VERSION 5.8 ;
BUSBITCHARS "[]" ;
DIVIDERCHAR "/" ;
UNITS
    DATABASE MICRONS 1000 ;
END UNITS

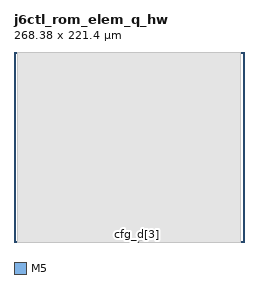
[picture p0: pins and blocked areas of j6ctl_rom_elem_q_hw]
MACRO j6ctl_rom_elem_q_hw
  FOREIGN ot_v41_rom_elem_q_qxpq_w10_gb_hw 0 0 ;
  CLASS BLOCK ;
  SIZE 268.38 BY 221.4 ;
  PIN bank_free
    DIRECTION OUTPUT ;
    USE SIGNAL ;
    PORT
      LAYER M5 ;
        RECT  142.752 0 142.776 0.084 ;
    END
  END bank_free
  PIN cfg_a[0]
    DIRECTION INPUT ;
    USE SIGNAL ;
    PORT
      LAYER M5 ;
        RECT  142.848 0 142.872 0.084 ;
    END
  END cfg_a[0]
  PIN cfg_a[1]
    DIRECTION INPUT ;
    USE SIGNAL ;
    PORT
      LAYER M5 ;
        RECT  142.944 0 142.968 0.084 ;
    END
  END cfg_a[1]
  PIN cfg_a[2]
    DIRECTION INPUT ;
    USE SIGNAL ;
    PORT
      LAYER M5 ;
        RECT  143.04 0 143.064 0.084 ;
    END
  END cfg_a[2]
  PIN cfg_a[3]
    DIRECTION INPUT ;
    USE SIGNAL ;
    PORT
      LAYER M5 ;
        RECT  143.136 0 143.16 0.084 ;
    END
  END cfg_a[3]
  PIN cfg_a[4]
    DIRECTION INPUT ;
    USE SIGNAL ;
    PORT
      LAYER M5 ;
        RECT  143.232 0 143.256 0.084 ;
    END
  END cfg_a[4]
  PIN cfg_d[0]
    DIRECTION INPUT ;
    USE SIGNAL ;
    PORT
      LAYER M5 ;
        RECT  143.328 0 143.352 0.084 ;
    END
  END cfg_d[0]
  PIN cfg_d[10]
    DIRECTION INPUT ;
    USE SIGNAL ;
    PORT
      LAYER M5 ;
        RECT  144.288 0 144.312 0.084 ;
    END
  END cfg_d[10]
  PIN cfg_d[11]
    DIRECTION INPUT ;
    USE SIGNAL ;
    PORT
      LAYER M5 ;
        RECT  144.384 0 144.408 0.084 ;
    END
  END cfg_d[11]
  PIN cfg_d[12]
    DIRECTION INPUT ;
    USE SIGNAL ;
    PORT
      LAYER M5 ;
        RECT  144.48 0 144.504 0.084 ;
    END
  END cfg_d[12]
  PIN cfg_d[13]
    DIRECTION INPUT ;
    USE SIGNAL ;
    PORT
      LAYER M5 ;
        RECT  144.576 0 144.6 0.084 ;
    END
  END cfg_d[13]
  PIN cfg_d[14]
    DIRECTION INPUT ;
    USE SIGNAL ;
    PORT
      LAYER M5 ;
        RECT  144.672 0 144.696 0.084 ;
    END
  END cfg_d[14]
  PIN cfg_d[15]
    DIRECTION INPUT ;
    USE SIGNAL ;
    PORT
      LAYER M5 ;
        RECT  144.768 0 144.792 0.084 ;
    END
  END cfg_d[15]
  PIN cfg_d[16]
    DIRECTION INPUT ;
    USE SIGNAL ;
    PORT
      LAYER M5 ;
        RECT  144.864 0 144.888 0.084 ;
    END
  END cfg_d[16]
  PIN cfg_d[17]
    DIRECTION INPUT ;
    USE SIGNAL ;
    PORT
      LAYER M5 ;
        RECT  144.96 0 144.984 0.084 ;
    END
  END cfg_d[17]
  PIN cfg_d[1]
    DIRECTION INPUT ;
    USE SIGNAL ;
    PORT
      LAYER M5 ;
        RECT  143.424 0 143.448 0.084 ;
    END
  END cfg_d[1]
  PIN cfg_d[2]
    DIRECTION INPUT ;
    USE SIGNAL ;
    PORT
      LAYER M5 ;
        RECT  143.52 0 143.544 0.084 ;
    END
  END cfg_d[2]
  PIN cfg_d[3]
    DIRECTION INPUT ;
    USE SIGNAL ;
    PORT
      LAYER M5 ;
        RECT  143.616 0 143.64 0.084 ;
    END
  END cfg_d[3]
  PIN cfg_d[4]
    DIRECTION INPUT ;
    USE SIGNAL ;
    PORT
      LAYER M5 ;
        RECT  143.712 0 143.736 0.084 ;
    END
  END cfg_d[4]
  PIN cfg_d[5]
    DIRECTION INPUT ;
    USE SIGNAL ;
    PORT
      LAYER M5 ;
        RECT  143.808 0 143.832 0.084 ;
    END
  END cfg_d[5]
  PIN cfg_d[6]
    DIRECTION INPUT ;
    USE SIGNAL ;
    PORT
      LAYER M5 ;
        RECT  143.904 0 143.928 0.084 ;
    END
  END cfg_d[6]
  PIN cfg_d[7]
    DIRECTION INPUT ;
    USE SIGNAL ;
    PORT
      LAYER M5 ;
        RECT  144 0 144.024 0.084 ;
    END
  END cfg_d[7]
  PIN cfg_d[8]
    DIRECTION INPUT ;
    USE SIGNAL ;
    PORT
      LAYER M5 ;
        RECT  144.096 0 144.12 0.084 ;
    END
  END cfg_d[8]
  PIN cfg_d[9]
    DIRECTION INPUT ;
    USE SIGNAL ;
    PORT
      LAYER M5 ;
        RECT  144.192 0 144.216 0.084 ;
    END
  END cfg_d[9]
  OBS
    LAYER RVTN ;
     RECT  4.32 0 264.06 221.4 ;
    LAYER RVTP ;
     RECT  4.32 0 264.06 221.4 ;
    LAYER M1 ;
     RECT  4.32 0 264.06 221.4 ;
    LAYER M2 ;
     RECT  4.32 0 264.06 221.4 ;
    LAYER M3 ;
     RECT  4.32 0 264.06 221.4 ;
    LAYER M4 ;
     RECT  141.109 1.056 141.829 1.08 ;
     RECT  140.785 0.048 142.081 0.072 ;
     RECT  141.505 0.192 142.081 0.216 ;
     RECT  141.829 1.056 142.883 1.128 ;
     RECT 142.0810 0.1950 142.9130 0.2160 ;
     RECT 142.0810 0.0480 142.6410 0.1950 ;
     RECT  142.297 0.528 143.053 0.552 ;
     RECT  142.933 1.728 143.057 1.752 ;
     RECT  142.883 1.056 143.459 1.08 ;
     RECT  143.221 1.728 143.597 1.752 ;
     RECT  142.189 0.336 143.629 0.36 ;
     RECT  143.053 0.48 143.629 0.552 ;
     RECT  143.629 0.336 143.651 0.552 ;
     RECT  143.651 0.336 143.653 0.504 ;
     RECT  140.713 0.816 143.747 0.84 ;
     RECT 143.6530 0.1950 143.8130 0.5040 ;
     RECT 143.8130 0.1950 143.8570 0.5040 ;
     RECT  143.665 1.104 143.917 1.128 ;
     RECT  143.857 0.24 144.035 0.504 ;
     RECT  144.035 0.24 144.131 0.264 ;
     RECT  144.035 0.432 144.323 0.504 ;
     RECT  143.917 1.056 144.515 1.128 ;
     RECT  144.515 1.056 144.611 1.08 ;
     RECT  143.773 1.68 144.661 1.704 ;
     RECT  144.323 0.432 144.709 0.456 ;
     RECT  144.661 1.68 144.949 1.752 ;
     RECT  144.949 1.68 144.997 1.8 ;
     RECT  144.709 0.432 145.045 0.552 ;
     RECT  144.997 1.584 145.141 1.8 ;
     RECT  143.521 1.968 146.531 1.992 ;
     RECT  144.757 1.152 146.549 1.176 ;
     RECT  144.889 1.392 148.355 1.416 ;
     RECT 142.6410 0.0480 142.8870 0.0720 ;
     RECT 142.6410 0.1440 142.8870 0.1680 ;
     RECT 142.6410 0.1920 142.8870 0.1950 ;
     RECT 142.7210 0.0960 142.8050 0.1200 ;
     RECT 142.7370 0.0480 142.9830 0.0720 ;
     RECT 142.7370 0.0960 142.8050 0.1200 ;
     RECT 142.7370 0.1440 142.9830 0.1680 ;
     RECT 142.7370 0.1920 142.9130 0.1950 ;
     RECT 142.8330 0.0480 143.0790 0.0720 ;
     RECT 142.8330 0.1440 143.0790 0.1680 ;
     RECT 142.8330 0.1920 142.9130 0.1950 ;
     RECT 142.8730 0.0960 142.8870 0.1200 ;
     RECT 142.8730 0.0960 142.9830 0.1200 ;
     RECT 142.8730 0.0960 143.0790 0.1200 ;
     RECT 142.9290 0.0480 143.1750 0.0720 ;
     RECT 142.9290 0.0960 143.1750 0.1200 ;
     RECT 142.9290 0.1440 143.1750 0.1680 ;
     RECT 143.0250 0.0480 143.2710 0.0720 ;
     RECT 143.0250 0.0960 143.2710 0.1200 ;
     RECT 143.0250 0.1440 143.2710 0.1680 ;
     RECT 143.1210 0.0480 143.3670 0.0720 ;
     RECT 143.1210 0.0960 143.3670 0.1200 ;
     RECT 143.1210 0.1440 143.3670 0.1680 ;
     RECT 143.2170 0.0480 143.4630 0.0720 ;
     RECT 143.2170 0.0960 143.4630 0.1200 ;
     RECT 143.2170 0.1440 143.4630 0.1680 ;
     RECT 143.3130 0.0480 143.5590 0.0720 ;
     RECT 143.3130 0.0960 143.5590 0.1200 ;
     RECT 143.3130 0.1440 143.5590 0.1680 ;
     RECT 143.4090 0.0480 143.6550 0.0720 ;
     RECT 143.4090 0.0960 143.6550 0.1200 ;
     RECT 143.4090 0.1440 143.6550 0.1680 ;
     RECT 143.5050 0.0480 143.7510 0.0720 ;
     RECT 143.5050 0.0960 143.7510 0.1200 ;
     RECT 143.5050 0.1440 143.6990 0.1680 ;
     RECT 143.6010 0.0480 143.8130 0.0720 ;
     RECT 143.6010 0.0960 143.8470 0.1200 ;
     RECT 143.6010 0.1440 143.6990 0.1680 ;
     RECT 143.6970 0.0480 143.8130 0.0720 ;
     RECT 143.6970 0.0960 143.9390 0.1200 ;
     RECT 143.6970 0.1440 143.6990 0.1680 ;
     RECT 143.7730 0.1440 143.8470 0.1680 ;
     RECT 143.7730 0.1440 143.8570 0.1680 ;
     RECT 143.7930 0.0480 143.8130 0.0720 ;
     RECT 143.7930 0.0960 143.9390 0.1200 ;
     RECT 143.7930 0.1440 143.8570 0.1680 ;
     RECT 143.8890 0.0960 143.9390 0.1200 ;
    LAYER M5 ;
     RECT 144.0000 0.1990 146.3280 0.2750 ;
     RECT  144 0.275 144.024 0.371 ;
     RECT  144.192 0.275 146.328 0.467 ;
     RECT  144.192 0.467 146.136 0.515 ;
     RECT 142.8480 0.1990 143.7360 0.5630 ;
     RECT  144.384 0.515 146.136 0.563 ;
     RECT  144.384 0.563 145.56 0.611 ;
     RECT  143.712 0.563 143.736 0.851 ;
     RECT  142.848 0.563 143.544 1.091 ;
     RECT  144.384 0.611 144.984 1.091 ;
     RECT  142.848 1.091 143.352 1.139 ;
     RECT  144.384 1.091 144.504 1.139 ;
     RECT  144.672 1.091 144.984 1.187 ;
     RECT  142.944 1.139 143.352 1.763 ;
     RECT  144.672 1.187 144.696 1.763 ;
     RECT  144.864 1.187 144.984 1.763 ;
     RECT  144.96 1.763 144.984 1.811 ;
     RECT  144.384 1.139 144.408 2.291 ;
     RECT  143.04 1.763 143.16 2.867 ;
     RECT  143.52 1.091 143.544 3.443 ;
     RECT  143.328 1.763 143.352 3.971 ;
     RECT  144.192 0.515 144.216 5.171 ;
     RECT 142.7520 0.0840 142.7760 0.1310 ;
     RECT 142.8480 0.0840 142.8720 0.1990 ;
     RECT 142.9440 0.0840 142.9680 0.1990 ;
     RECT 143.0400 0.0840 143.0640 0.1990 ;
     RECT 143.1360 0.0840 143.1600 0.1990 ;
     RECT 143.2320 0.0840 143.2560 0.1990 ;
     RECT 143.3280 0.0840 143.3520 0.1990 ;
     RECT 143.4240 0.0840 143.4480 0.1990 ;
     RECT 143.5200 0.0840 143.5440 0.1990 ;
     RECT 143.6160 0.0840 143.6400 0.1990 ;
     RECT 143.6640 0.1330 143.6880 0.1990 ;
     RECT 143.7120 0.0840 143.7360 0.1990 ;
     RECT 143.8080 0.0840 143.8320 0.1790 ;
     RECT 143.9040 0.0840 143.9280 0.1310 ;
     RECT 144.0000 0.0840 144.0240 0.1990 ;
     RECT 144.0960 0.0840 144.1200 0.1990 ;
     RECT 144.1920 0.0840 144.2160 0.1990 ;
     RECT 144.2880 0.0840 144.3120 0.1990 ;
     RECT 144.3840 0.0840 144.4080 0.1990 ;
     RECT 144.4800 0.0840 144.5040 0.1990 ;
     RECT 144.5760 0.0840 144.6000 0.1990 ;
     RECT 144.6720 0.0840 144.6960 0.1990 ;
     RECT 144.7680 0.0840 144.7920 0.1990 ;
     RECT 144.8640 0.0840 144.8880 0.1990 ;
     RECT 144.9600 0.0840 144.9840 0.1990 ;
     RECT 142.7520 0.0000 142.7760 0.0840 ;
     RECT 142.8480 0.0000 142.8720 0.0840 ;
     RECT 142.9440 0.0000 142.9680 0.0840 ;
     RECT 143.0400 0.0000 143.0640 0.0840 ;
     RECT 143.1360 0.0000 143.1600 0.0840 ;
     RECT 143.2320 0.0000 143.2560 0.0840 ;
     RECT 143.3280 0.0000 143.3520 0.0840 ;
     RECT 143.4240 0.0000 143.4480 0.0840 ;
     RECT 143.5200 0.0000 143.5440 0.0840 ;
     RECT 143.6160 0.0000 143.6400 0.0840 ;
     RECT 143.7120 0.0000 143.7360 0.0840 ;
     RECT 143.8080 0.0000 143.8320 0.0840 ;
     RECT 143.9040 0.0000 143.9280 0.0840 ;
     RECT 144.0000 0.0000 144.0240 0.0840 ;
     RECT 144.0960 0.0000 144.1200 0.0840 ;
     RECT 144.1920 0.0000 144.2160 0.0840 ;
     RECT 144.2880 0.0000 144.3120 0.0840 ;
     RECT 144.3840 0.0000 144.4080 0.0840 ;
     RECT 144.4800 0.0000 144.5040 0.0840 ;
     RECT 144.5760 0.0000 144.6000 0.0840 ;
     RECT 144.6720 0.0000 144.6960 0.0840 ;
     RECT 144.7680 0.0000 144.7920 0.0840 ;
     RECT 144.8640 0.0000 144.8880 0.0840 ;
     RECT 144.9600 0.0000 144.9840 0.0840 ;
  END
END j6ctl_rom_elem_q_hw

END LIBRARY
